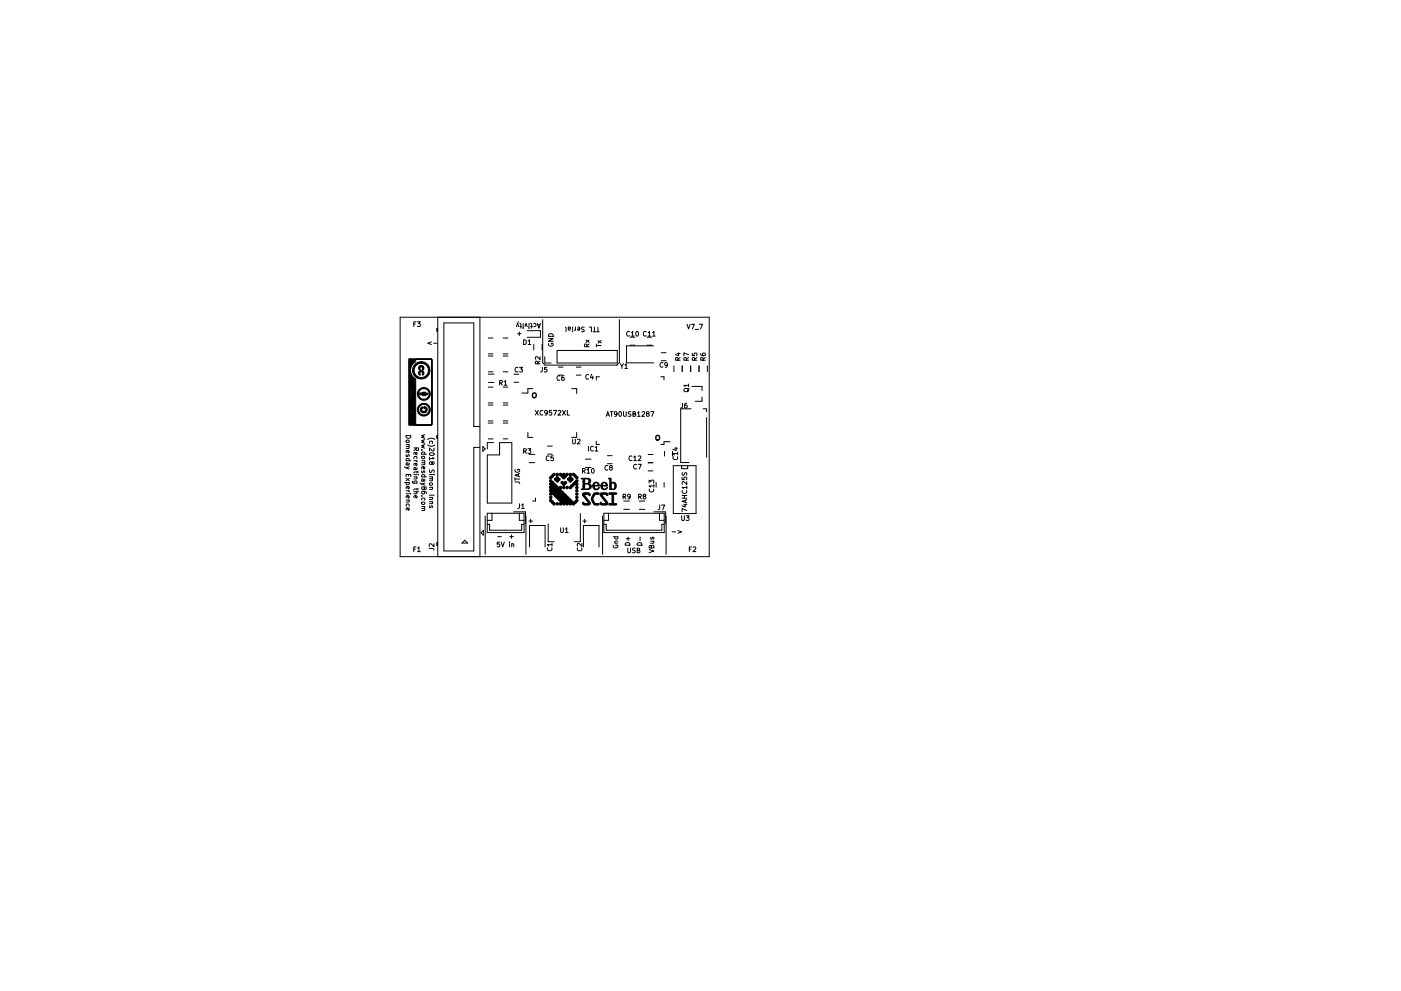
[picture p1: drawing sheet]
<svg xmlns="http://www.w3.org/2000/svg" width="297mm" height="210mm" viewBox="0 0 297 210" stroke-linecap="round" stroke-linejoin="round" font-family="sans-serif">
<g fill="none" stroke="#000" stroke-width=".21">
<path d="M84.8 67.3h65.6v50.8h-65.6zM87.7 68.8h.4M88.2 68.3h-.5v1M88.5 68.3h.6l-.3 .4 .3 .1v.4h-.6M91.5 72.5l-.8 .3 .8 .3M91.9 72.8h.8M92.7 69.7v.5M92.8 67.3v50.8M92.8 69.7h-.2v.5h.2M101.8 67.3v50.8M103.5 78.9h1M103.5 75.5h1"/>
<path d="M103.5 75.1h1M103.5 71.7h1M103.5 79.4h1.2M106.7 78.9h1M106.7 75.5h1M106.7 75.1h1M106.7 71.7h1M109 79.4h1M109.7 70.8h.8M109.7 68.6l.3 .7M109.8 78a.44 .44 0 0 0-.6 .4 .44 .44 0 0 0 .6 .4M110 68.3l-.5 1"/>
<path d="M110.1 70.4v.8M110.1 77.9h.7l-.4 .4 .3 .1v.4h-.6M110.2 68.6l.2 .2v.8M110.2 69.3h.4M110.9 69.5v.1M110.9 68.6v.7M111 72.1a.51 .51 0 0 1 .6 .5 .51 .51 0 0 1-.6 .5zM111.3 69.3l.2-.7 .3 .7M111.8 70.2h2.8v1.4h-2.8M112 72.4l.3-.3v1M112 73.1h.5M112.2 69.5v.1"/>
<path d="M112.2 68.6v.7M112.5 68.6l.2 .2v.8M112.5 69.3h.4M113.2 68.7l.2-.1 .2 .2-.1 .4h-.3M113.2 73.1v1.2M113.9 68.6l.4 1 .3-1M114 68.9h.5M114 77.2v-.5h-.4l-.1 .5h1M114.5 75.7v.6l-.7-.6-.3 .2 .1 .3M114.5 76.6l-.5 .3M114.9 73.1v1.2M115 77.9l-.1 .9-.3 .1"/>
<path d="M115.1 67.8v9.2l.5 .5h15.2l.5-.5v-9.2M115.5 75.7v1.3h1.3M115.9 77.9h-.4l-.1 .5h.5v.4h-.5M116.3 71.8h1l-1 .6h1M116.3 72.9a.45 .45 0 0 0 .5 .6 .45 .45 0 0 0 .4-.7h-.3v.2M116.3 71a.54 .54 0 0 1 .7-.2 .54 .54 0 0 1 .3 .6h-1zM118.1 74.4h12.8v2.6h-12.8zM118.4 79.6h1M118.4 77.9h1M118.7 79.8a.44 .44 0 0 0-.6 .4 .44 .44 0 0 0 .6 .4M119.6 79.7l-.5 .2v.6l.2 .2 .3-.1v-.5h-.3l-.2 .2M119.9 69.4l.1 .1v.9"/>
<path d="M120.5 69.4v.6h.4M120.5 69.4h.3l.2 .1-.1 .2-.4 .1M121.4 70.3v.1M121.4 69.4v.7M122 69.9l-.3 .2M122 69.4v.7M122.2 79.6h1M122.2 77.9h1M122.5 69.4h.3l.1 .1v.5h-.4l-.1-.2 .5-.1M123.9 69.4l-.6 .1a.42 .42 0 0 0 .5 .5v.3h-.5M124.2 72.1l.7 .6M124.4 73.6v-.5l-.4-.1-.1 .6h1"/>
<path d="M124.8 79.6a.44 .44 0 0 0-.6 .4 .44 .44 0 0 0 .6 .4M124.9 73l-.5 .3M124.9 72.1l-.7 .6M124.9 69.4h.5v1M125.4 79.4l-.2 .7h.6M125.7 79.8v.7M125.7 70.4h.6M126 69.4v1M126.5 73v.6M126.5 73.3h1M126.5 70.4h.6M126.8 69.4v1"/>
<path d="M126.8 72.2l.7 .6M127.1 79.9h-.7v.7M127.5 72.2l-.7 .6M131.5 77.2l.4 .5 .3-.5M131.9 77.7v.5M132.5 77.5l.3-.3v1M132.5 78.2h.5M133.5 70.4a.44 .44 0 0 0-.7 .4 .44 .44 0 0 0 .7 .4M133.6 71.5h1M133.6 73.2h1M133.9 70.6l.2-.3v1M133.9 71.3h.5"/>
<path d="M134.9 70.4l.1-.1a.49 .49 0 0 1 .4 .5 .49 .49 0 0 1-.5 .5l-.1-.4zM137 70.4a.44 .44 0 0 0-.6 .4 .44 .44 0 0 0 .6 .4M137.2 71.5h1M137.2 73.2h1M137.4 70.6l.3-.3v1M137.4 71.3h.6M138.4 70.6l.2-.3v1M138.4 71.3h.5M138.6 73.4h-5.8v3.6h5.8M140.1 79.9h.7v.7M140.2 76.5h1M140.2 74.8h1"/>
<path d="M140.5 77a.44 .44 0 0 0-.6 .4 .44 .44 0 0 0 .6 .4M141.5 77.3l-.2 .2h-.3v-.5l.3-.1 .2 .2v.6l-.5 .2M142.9 77.6v1.2M143.5 75h.7M143.7 76.4v-.5h-.4l-.1 .5h1M143.9 74.9v.6l-.7-.3M144.2 75.9l-.5 .3M144.6 77.6v1.2M145.5 76.4v-.5h-.4l-.1 .5h1M145.7 68.8l.3 1 .3-1M146 75.3l-1-.4v.6M146 75.9l-.5 .3"/>
<path d="M146.4 77.6v1.2M146.6 68.8h.6l-.4 1M146.8 74.9v.5l.4 .1v-.5l.5-.1v.6M147.3 76.4l-.1-.5h-.3l-.1 .5h1M147.4 69.9h.7M147.8 75.9l-.5 .3M148.2 77.6v1.2M148.3 68.8h.6l-.4 1M148.6 75l.2 .4 .6 .1 .2-.2-.1-.4-.5 .1-.1 .3 .2 .2M149.1 76.4l-.1-.5h-.4v.5h1M149.6 75.9l-.5 .3M150 77.6v1.2"/>
<path d="M85.8 99l1 .5M86.1 92.4h1a.51 .51 0 0 1-.5 .6 .51 .51 0 0 1-.5-.6zM86.1 97.8h1M86.1 94.3h.7M86.1 93.5l.5-.1 .2 .3-.2 .2h-.3l-.2-.2zM86.1 96.5v.3h.3l.2-.3 .2 .1-.1 .2M86.1 97.8v-.3l.2-.2 .4 .1v.4M86.1 98.7v-.4l.1-.1h.2l.1 .5M86.4 95.6l.1 .5 .2-.1 .1-.2-.2-.2-.5 .1v.3M86.6 94.8l.1 .3-.6 .1M86.7 94.3v.4l-.6 .1M86.7 98.2v.4l-.6 .1"/>
<path d="M86.8 99l-.7 .3M87.7 95h1v.6l-.4-.1-.1-.5M87.7 97.8h.7M87.8 97.3l-.1-.3 .2-.2 .5 .1v.4M88.1 96l.1 .5 .2-.1v-.3l-.1-.1h-.5v.4M88.1 98.3l.1 .5h.2v-.3l-.1-.2-.5 .1v.4M88.2 97.8l.2 .2M88.2 95.3l-.5 .3M88.4 99.2v.3l-.1 .2h-.6v-.4l.4-.1 .1 .5M88.4 100v.4M89.4 95.5h.1M89.4 96.4h1"/>
<path d="M89.4 97.8h.7M89.4 96.4v-.3l.2-.2 .4 .1v.4M89.4 96.9l.5-.1 .2 .3-.2 .2h-.3l-.2-.2zM89.4 99.9v.4h.3l.2-.4 .2 .1-.1 .3M89.7 99l.1 .5h.2l.1-.3-.2-.2-.5 .1v.4M89.9 98.2l.1 .4h-.6M90 97.8v.3l-.6 .1M90.1 92.2l-.7 .2 .5 .2-.5 .2 .7 .2M90.1 93.3l-.7 .2 .5 .2-.5 .1 .7 .2M90.1 94.3l-.7 .2 .5 .2-.5 .2 .7 .2M90.7 93.3a1.15 1.15 0 0 1 1.5 0M90.7 94.4a1.15 1.15 0 0 0 1.5 0"/>
<path d="M91 97v.6M91.1 94.1l-.1-.3 .2-.2 .5 .1v.4M91.1 96.2a.49 .49 0 0 1 .6-.2 .49 .49 0 0 1 .3 .5 .49 .49 0 0 1-.6 .2 .49 .49 0 0 1-.3-.5zM91.1 99.7v.5a.42 .42 0 0 0 .6-.5l.3 .1v.5M91.6 98.2l.4-.2v.4l-.3 .1-.3-.5-.4 .2 .2 .3 .4-.2M91.8 97l.2 .3h-1M92 95.1v.4l-.2 .2-.8-.6v.6M92.7 92.5v.5M92.8 92.5h-.2v.5h.2M101.8 90.5h-1.3v-22h-6.4v48.4h6.4v-22h1.3M102.4 94.7l.5 .5-.5 .6zM103.3 96.5h2.6v-2.6h2.6v12.8h-5.2z"/>
<path d="M103.5 89.3h1M103.5 85.9h1M103.5 85.5h1M103.5 82.1h1M103.5 93.1h1M103.5 89.8h1M103.5 81.1h1.2M104.6 93.9h-1.3v1.3M105.9 81.3l.5-.1 .1-.4-.6-.1v1M106.2 81.3l.3 .4M106.7 89.3h1M106.7 85.9h1"/>
<path d="M106.7 85.5h1M106.7 82.1h1M106.7 93.1h1M106.7 89.8h1M106.9 81l.3-.3v1M106.9 81.7h.6M109 81.1h1M109.2 99.6a.45 .45 0 0 0 .5 .6 .45 .45 0 0 0 .4-.6h-.3v.2M111 95.7h.5v-.4l-.5-.1v1M111.3 95.7l.3 .5M111.9 91.7v1.1h1.1M111.9 95.2h.6l-.3 .4 .3 .1v.4h-.6"/>
<path d="M112.2 96.4h1.2M112.2 98.2h1.2M113 82.4h-1.1v1h-1.3M113.5 87.1l.6 1M114.1 87.1l-.6 1M115.1 87.2a.44 .44 0 0 0-.6 .4 .44 .44 0 0 0 .6 .4M116 87.5l-.1 .2-.3-.1-.1-.4 .4-.1 .1 .2v.5l-.4 .3M116.1 96.3h1M116.1 94.6h1M116.4 96.8a.44 .44 0 0 0-.6 .4 .44 .44 0 0 0 .6 .4M117 87.1h-.5l-.1 .5 .5-.1 .1 .5h-.6M117.3 96.7h-.5v.5h.5v.4h-.5"/>
<path d="M117.3 87.1h.7l-.4 1M118.3 87.2l.4-.1 .2 .3-.6 .7h.6M119.2 87.1l.7 1M119.9 87.1l-.7 1M120.3 87.1v1h.5M121.2 82.4h1.1v1.1M121.4 93.2v.8l.2 .2 .4-.2v-.8M122.3 91.7v1.1h-1.1M122.4 93.3l.4-.1 .2 .3-.6 .7h.6M123.5 99.9h.5v-.4l-.5-.1v1M123.7 99.9l.4 .5M124.1 97.4h1.2"/>
<path d="M124.1 99.2h1.2M124.5 99.7l.2-.3v1M124.8 94.7v1M125.5 99.5l.1-.1a.49 .49 0 0 1 .4 .5 .49 .49 0 0 1-.5 .4l-.1-.3zM125.8 94.8a.44 .44 0 0 0-.6 .4 .44 .44 0 0 0 .6 .4M126.2 95l.3-.3v1M126.2 95.7h.6M126.4 93.6v.7h.7M128.5 88.3l.4-1 .3 1M128.6 88h.5M128.8 96.7h1M128.8 98.4h1"/>
<path d="M128.9 98.9a.44 .44 0 0 0-.7 .4 .44 .44 0 0 0 .7 .4M129.4 87.3h.6M129.4 99.2l-.1-.3 .4-.1 .1 .3-.6 .3 .2 .4 .4-.2-.2-.4M129.7 87.3v1M130.8 87.8l-.2 .1h-.3v-.5l.3-.1 .2 .2v.6l-.5 .2M131.3 87.4l.1-.1a.49 .49 0 0 1 .4 .5 .49 .49 0 0 1-.5 .5l-.1-.4zM132.2 87.3v.8l.2 .2 .4-.2v-.8M133.8 87.4h-.6a.42 .42 0 0 0 .5 .5v.4h-.5M134 96.8a.44 .44 0 0 0-.6 .4 .44 .44 0 0 0 .6 .4M134.2 87.8h.4l.1-.4-.5-.1v1h.4l.2-.3-.3-.2M134.4 97l.2-.3v1M134.4 97.7h.5"/>
<path d="M135 98.6a.44 .44 0 0 0-.7 .4 .44 .44 0 0 0 .7 .4M135.2 87.6l.2-.3v1M135.2 88.3h.5M135.3 98.5h.7l-.5 1M135.3 96.8l.4-.1 .2 .3-.6 .7h.6M136.1 87.4l.4-.1 .2 .3-.6 .7h.6M137.2 87.8l-.1-.4h.4l.1 .3-.5 .2 .1 .4 .4-.2-.2-.3M137.4 99.9h1M137.4 98.2h1M137.4 96.4h1M137.4 98.1h1M138 87.3h.6l-.4 1"/>
<path d="M140.9 95.8v1M142.1 93.7h-1.3v.6h-.7M142.6 95.8v1M142.7 98.8h4.9v10.2h-4.9zM142.8 96.9a.44 .44 0 0 0 .4 .6 .44 .44 0 0 0 .4-.6M143 95.1h.7M143.4 95v.6l-.8-.3M143.7 96.2h-1l.3 .3M143.7 96v.5M144.5 98.8v.6h1.3v-.6M144.7 85.6v.8l-.4 .2M145 82.6l.3-.2 .6 .1 .1 .4-.3 .2h-.6z"/>
<path d="M145.6 85.6l-.4 .2-.1 .6 .2 .2 .4-.1-.1-.5-.3-.1-.2 .2M146 81.8h-1l.3 .3M146 81.5v.6M146.1 82.4l-.3 .5M146.5 86.7h-2.2v11.4h1.8M146.7 82h2.1v.9M148.8 84.2v.9h-1.4M149.1 86.7h.7v.7M149.8 88.6v8.4M85.8 102.4h1M86.1 101.1v-.4h1v.4M86.1 101.5l.7 .5"/>
<path d="M86.1 104.1h.7M86.1 104.8h.7M86.1 106.1h.7M86.1 102.4v.3l.2 .1h.4v-.4M86.1 107.4v-.3l.2-.2 .4 .1v.4M86.4 103.2l.1 .5h.2l.1-.3-.2-.2-.5 .1v.4M86.4 105.2l.1 .5 .2-.1 .1-.3-.2-.1h-.5v.4M86.4 107.8l.1 .5 .2-.1 .1-.3-.2-.1h-.5v.4M86.6 104.1l.2 .3M86.6 100.7v.3M86.7 106.1v.4h-.6M86.8 101.5l-.7 .5"/>
<path d="M87 104.8h.1M87.5 102.1l-.1 .2 .2 .2h.8M87.7 116.5h.4M87.7 101.2h.7M87.7 100.7h.7M87.7 104.3h1M87.8 102.5l-.1-.3 .2-.2 .5 .1v.4M88.1 105.2l.1 .5 .2-.1v-.3l-.1-.1h-.5v.4M88.2 116h-.5v1M88.3 101.2l.1 .4h-.7M88.3 104.3l.1 .4-.7 .1M88.4 103.6v.4"/>
<path d="M88.5 116.3l.3-.3v1M88.5 117h.6M88.7 100.7h.1M88.7 100.1h-.8l-.2 .3M88.7 103.8h-.8l-.2 .2M89.1 102.5l1 .4M89.4 105.2h.1M89.4 101.2h1M89.4 107.5h.7M89.4 101.2v-.3l.2-.2 .4 .1v.4M89.4 102.1v-.3l.1-.2 .2 .1 .1 .4M89.4 106.1v-.3l.2-.1 .4 .1v.3"/>
<path d="M89.4 106.6l.5-.1 .2 .3-.2 .2h-.3l-.2-.2zM89.8 104.2l.2 .2v.3l-.5 .1-.1-.4 .2-.2 .6 .1 .2 .4M89.9 107.9l.1 .4h-.6M90 103.5l.3-.2 .1 .5h-.3l-.3-.5-.4 .2 .2 .3 .4-.1M90 107.5v.3l-.6 .1M90 101.7v.3l-.6 .1M90.1 102.5l-.7 .2M91 116.4h.9l.1 .3M91 100.7h.7M91 101.2h.7M91 103.4h.7M91 105.1h1"/>
<path d="M91 105.5h.7M91 106.4h.7M91.1 107.3v.4h.2l.2-.4 .2 .1v.3M91.1 102.5h.5l.1 .4h-.6zM91.6 101.6l.1 .4h-.7M91.6 101.2l.1 .3-.7 .1M91.6 103.4l.1 .4h-.7M91.6 105.5l.1 .4-.7 .1M91.6 106.4l.1 .4-.7 .1M92 100.7h.1M92 115.4v.6l-.7-.6-.3 .1 .1 .4M92.7 115.2v.5"/>
<path d="M92.8 115.2h-.2v.5h.2M98.6 114.6l.6 .6h-1.2zM102.5 112.5v1l-.5-.5zM102.9 109.5v8.1M103.3 108.9h7.8v4.1h-7.8zM103.3 111.2h.5v1.3h6.8v-1.3h.5M104.3 108.9v1.5h-1M105.5 113.9h.8M105.9 115h-.5v.5l.5-.1v.5h-.5M106.3 115l.3 1 .3-1M108 115v.1M108 115.3v.7"/>
<path d="M108.1 113.9h.7M108.5 113.5v.7M108.5 115.4h.4v.6M108.5 115.3v.7M108.9 108.6h2.5v2.5M109.2 102.3h.8l.2 .3M109.2 101.3v.6M109.2 101.6h1M109.9 100.6v.5M110.1 108.9v1.5h1M110.2 106.9l-.1 .8-.3 .2M110.2 100.5l-1 .3 1 .4"/>
<path d="M110.6 107.2l.3-.3v1M110.6 107.9h.6M111.5 109.5v8.1M112.1 110.6h.8M112.3 116v-4.5h3.3v4.5M112.5 110.2v.7M113.5 105.7v.6h-.6M116.1 116.2a.44 .44 0 0 0 .4 .7 .44 .44 0 0 0 .4-.7M116.2 111.2v3.7h1.3M117 115.6h-1l.3 .3M117 115.3v.6M118.9 112v.8l.2 .2 .3-.2v-.8"/>
<path d="M119.9 112.3l.3-.3v1M119.9 113h.5M122.5 116.2a.44 .44 0 0 0 .4 .7 .44 .44 0 0 0 .4-.7M123 108.9v6h-1.2M123.4 115.3v.6l-.7-.6-.3 .2 .1 .4M123.6 110.6h.7M123.7 116v-4.5h3.3v4.5M124 110.2v.7M124.5 100.4h.5M127.8 109.5v8.1M128 108.9h12.8v4.1h-12.8zM128 111.2h.5v1.3h11.8v-1.3h.5"/>
<path d="M129 108.9v1.5h-1M130 113.9h1M130.1 115.7a.45 .45 0 0 0 .4 .6 .45 .45 0 0 0 .4-.6h-.3v.1M130.3 115.2h.7M130.4 113.9l-.1 .3 .2 .2 .5-.1v-.4M131 114.8h-.6v.4M132.1 105.4l.5-.1v-.3l-.5-.1v1M132.2 108.1h1.2M132.2 106.3h1.2M132.3 105.4l.4 .5M132.6 115.3a.54 .54 0 0 1 .6-.2 .54 .54 0 0 1 .3 .6h-1zM132.8 114.3h.7"/>
<path d="M133.1 116.3v.8l.2 .2 .4-.2v-.8M133.2 113.9v.8M133.6 105.3l-.2 .2-.2-.1-.1-.4 .3-.1 .2 .1v.6l-.4 .3M134.7 116.3l-.5 .1a.42 .42 0 0 0 .4 .5v.3h-.5M135.1 116.8l.4-.1 .1-.3-.5-.1v1h.4l.2-.3-.3-.2M135.1 115.3a.54 .54 0 0 1 .7-.2 .54 .54 0 0 1 .3 .6h-1zM135.4 105.4l.5-.1v-.3l-.5-.1v1M135.5 108.1h1.2M135.5 106.3h1.2M135.6 105.4l.4 .5M135.7 113.9v.8M136.5 105.3l-.1-.3 .4-.1 .1 .3-.5 .3 .1 .4 .4-.2-.2-.4"/>
<path d="M137.6 116.6l1 .3-1 .4M137.6 102.5v-.6l.4 .3 .1-.3h.4v.6M137.7 103.8a.44 .44 0 0 0 .4 .6 .44 .44 0 0 0 .4-.6M138 114.8h.6M138 114l.1 .4 .2-.4h.3v.4M138.1 115.9l.2-.2 .3 .2v.4h-1l.1-.5h.4v.5M138.5 114.8l.1 .4-.6 .1M138.6 108.6h2.5v2.5M138.6 103.1h-1l.3 .3M138.6 102.8v.6M139.1 102.4v1M139.8 108.9v1.5h1"/>
<path d="M139.9 107.1l-.1 .9-.3 .1M140.3 107.1h.6l-.4 1M140.8 102.4v1M141.2 109.5v8.1M142.5 112.8h.8M143.7 112.6l.8 .2-.8 .3M144.5 109.4v.8l.2 .2 .4-.2v-.8M144.6 101.3v.4l.5 .1-.1-.5h.5v.5M144.6 105.7h1M144.6 105.1h1M144.7 100.3v.5a.42 .42 0 0 0 .5-.5l.4 .1v.4M144.7 104.1a.44 .44 0 0 0 .4 .6 .44 .44 0 0 0 .4-.6"/>
<path d="M144.9 107.1h.7M145.1 105.1v.6M145.3 106.9v.7l-.7-.3M145.3 106.1v.5M145.5 109.4h.6l-.3 .4 .2 .1v.4h-.5M145.6 108.3l-1-.4v.7M145.6 106l-1 .4 1 .3M145.6 103.4h-1l.3 .3M145.6 102.2v.6l-.7-.6-.3 .2 .1 .3M145.6 103.1v.6M146.1 116.5h.4M146.6 116h-.5v1"/>
<path d="M147 116.1l.3-.1 .2 .3-.6 .7h.6"/>
</g>
<path d="M113 83.5l.2-.1 .4 .1 .1 .6-.2 .2-.3 .1-.2-.2zM139.1 92.5l.2-.1 .5 .1v.6l-.1 .2-.4 .1-.2-.2z" fill="none" stroke="#000" stroke-width=".3"/>
<g fill="#000" stroke="#000" stroke-width=".21">
<path d="M88.9 78.8a.53 .53 0 0 1 .8-.1 .53 .53 0 0 1-.1 .8l-.1-.1a.29 .29 0 0 0 .1-.4 .29 .29 0 0 0-.4 0 .29 .29 0 0 0-.1 .4l-.1 .2-.2-.2zM88.9 77.7a.57 .57 0 0 1 .8 0 .57 .57 0 0 1-.1 .9l-.1-.2a.29 .29 0 0 0 .1-.4 .29 .29 0 0 0-.4-.1 .29 .29 0 0 0-.1 .4v.2a.43 .43 0 0 1-.4-.3 .43 .43 0 0 1 .2-.5zM88.1 77.3l.9-.5h.3v.3a1.52 1.52 0 0 0-1.3 2.3 1.52 1.52 0 0 0 2.7 0 1.52 1.52 0 0 0-1.3-2.3l-.1-.3a1.83 1.83 0 0 1 1.8 2.3 1.83 1.83 0 0 1-2.7 1.1 1.83 1.83 0 0 1-.3-2.9zM87.1 83h.2l-.1 .3zM87.3 87l.2 .1-.2 .1zM87.4 83h.2l-.1 .3zM89 83.4l.9-.2a.26 .26 0 0 1 .4 0 .26 .26 0 0 1 0 .4l-.1 .3h-.6v-.1h-.6zM89.3 86.4l.3-.1v.3a.38 .38 0 0 0-.1 .6 .38 .38 0 0 0 .6 0 .28 .28 0 0 0 .2-.3 .28 .28 0 0 0-.3-.2l-.2-.2 .2-.3 .1 .1a.71 .71 0 0 1 .3 1.1 .71 .71 0 0 1-1.1 .1 .71 .71 0 0 1 0-1.1zM88.9 86l.7-.4h.3v.2a1.13 1.13 0 0 0-1 1.6 1.13 1.13 0 0 0 1.9 .2 1.13 1.13 0 0 0-.7-1.8h-.2v-.2a1.36 1.36 0 0 1 1.3 1.7 1.36 1.36 0 0 1-2 .8 1.36 1.36 0 0 1-.3-2.1zM88.9 82.7l.7-.5h.2v.3a1.13 1.13 0 0 0-.9 1.6 1.13 1.13 0 0 0 1.9 .1 1.13 1.13 0 0 0-.8-1.7h-.2v-.3a1.36 1.36 0 0 1 1.4 1.7 1.36 1.36 0 0 1-2 .9 1.36 1.36 0 0 1-.3-2.1zM86.7 76.1h.3v7.1l.2 .3 .5-.1 .1-.2v.3l-.8 .3v.2h.2v2.1l-.3 .3 .2 .9-.1 .2 .4-.1a.25 .25 0 0 0 .4-.3 .24 .24 0 0 0-.4-.2l-.4-.1v-.2a.36 .36 0 0 0 .4 0 .36 .36 0 0 0 .2-.3l-.1 .4a.28 .28 0 0 0 .3-.3 .28 .28 0 0 0-.4-.3 .28 .28 0 0 0-.2 .4h-.1l.1-.3v-2.2l.6 .2v-.2l-.3-.1 .2-.2 .1-.9h-.8v-6.7h4.4l-3.3 .1v.5a2.09 2.09 0 0 0 0 3.7v9.7h3.3v-14l.1 .1 .1 13v.8l-.1 .2h-4.8zM116.6 106h.3l.1 .3h.3v.4l.4 .1-.1 .3h-.3l-.1-.3-.3-.1v-.3l-.4-.1z"/>
<path d="M116.6 101.9h.3l.1 .3h.3v.3l.4 .1v.2l.3 .1v.3l.4 .1v.2h.2l.1-.3h.3l.1 .3-.4 .2v.2h.3l.1 .3 .3 .1v.3h.3l.1 .3 .2 .1 .1 .3 .4 .1v.2l.3 .1v.3h.3l.1 .3 .3 .1v.3h.2l.1-.3 .3-.1 .1-.3h.3v.4h-.3v.3l-.3 .1-.2 .4-.3-.1v-.3h-.2l-.2 .4-.3-.1v-.3h-.2l-.2 .4-.3-.1v-.3h-.2l-.2 .4-.3-.1v-.3h-.2l-.2 .3h-.2l-.1-.3 .4-.1v-.3h.4v.3h.2v-.3h.5v.3h.2v-.3h.5v.3h.2v-.3h-2.3l-.1-.3h.5v.2h.2v-.2h.5v.2h.2v-.2h.5v.2h.2v-.2h-2.3l-.1-.4h.4v.3h.3v-.3h.4v.3h.2v-.3h.5v.3h.2v-.3l-2.2 .1-.2-.4h.5v.2h.2v-.2h.5v.2h.2v-.2h.5v.2h.2v-.2h-2.3l-.1-.3h.4v.2h.3v-.2h.4v.2h.3v-.2h.4v.2h.2v-.2h-2.2l-.2-.2v-.2h.5v.2h.2v-.2h.5v.2h.2v-.2h.5v.2h.2v-.2h-2.3l-.1 .3h-.3l-.1-.3 .4-.1v-.2h.4v.2h.3v-.2h.4v.2h.3v-.2h.4v.2h.3v-.2l-2.4-.1-.1-.3h.5v.2h.2v-.2h.5v.2h.2v-.2h.5v.2h.2v-.2h-2.1l.4-.1v-.2h.4v.2h.3v-.2h.4v.2h.3v-.2l-1.7-.1-.1-.3h.5v.2h.2v-.2h.5v.2h.2v-.2h-1.4l.4-.1v-.2h.4v.2h.3v-.2l-1-.1-.1-.3h.5v.2h.2v-.2h-.7l.4-.1v-.2l-.4-.2zM116.9 100.8h.3l.2-.4 .3 .2-.1 .3h-.3v.3h-.3v.3l-.3 .1-.2-.3 .4-.2zM118 101.2l.3-.1 .1 .4 .4 .1-.6 .7-.7-.5 .1-.2h.4v.2h.3v-.2h-.7l.3-.1zM119 102.2h.3l.1 .3h.2l.1-.3 .2-.1 .2 .3-.6 .6-.2-.4-.3-.1zM118.7 100.5l.2-.1 .2 .4h.2v-.3l.3-.1 .2 .4h.2v-.3l.3-.1 .2 .3-1 .9-.6-.7h.5v.2h.2v-.2h-.9l-.1-.2zM120.7 101.2l.4-.1 .1 .4 .3 .2-.5 .6-.7-.5v-.2h.5v.2h.2v-.2h-.7l.4-.1zM121.4 100.5h.4l.1 .3h.2l.1 .3 .3 .1v.3l-.3 .1-.1-.4h-.3l-.1-.3-.3-.1zM121.8 102.2h.3l.1-.4 .3 .1v.2l-.3 .2v.2l.3 .1v.3l-.3 .1-.1-.4h-.2l-.1 .3-.3 .1-.1 .3h-.2l-.1 .3-.3 .1-.1-.4 .3-.1 .1-.3 .3-.1 .1-.3h.2zM123.2 101.5h1.5l.4 .2 .1 .5-.5 .4 .6 .4-.1 .6-.6 .3h-1.4v-.2h.4v-.5h.4v.4l.1 .1h.7l.2-.5-.2-.4-.3-.1h-.5v.5h-.4v-1.1h.4v.5h.5l.3-.3v-.4l-.2-.3h-.5l-.1 .5h-.4v-.4l-.4-.1zM123.6 104.7l1.2-.1 .3 .2-.1 .4-.3-.3h-.9l1.3 1.7v.3l-.1 .2-1.1 .1-.4-.3v-.2l.1-.2 .3 .3h.9l-1.3-1.7zM125.9 104.7l.3-.2 .8 .2-.1 .2h-.7l-.5 .9 .4 1h.8v.3h-.9l-.6-.9v-.6zM125.9 102.5l.6-.2 .4 .3 .2 .5h-1.1l.1 .5 .2 .1 .8-.2-.3 .3-.5 .1-.5-.3-.1-.6h1l.1-.1-.2-.4-.3-.1-.2 .2-.1 .4h-.3z"/>
<path d="M127.3 104.7l1.2-.1 .3 .2v.4l-.3-.3h-.9l1.2 1.7 .1 .3-.2 .2-1.1 .1-.3-.3-.1-.2 .2-.2 .2 .3h1l-1.3-1.7zM127.6 102.5l.6-.2 .4 .3 .2 .5h-1.1l.1 .5 .3 .1 .7-.2-.3 .3-.5 .1-.4-.3-.2-.6h1l.1-.1-.1-.4-.3-.1-.3 .2-.1 .4h-.3zM129 101.5l.6-.1v1.2l.6-.3 .4 .5-.1 .8-.4 .3-.4-.1a.21 .21 0 0 0-.2-.1 .21 .21 0 0 0-.2 .2v-.8h.3l.1 .5 .3 .2 .3-.3v-.6l-.1-.4h-.3l-.3 .1v.5h-.3v-1.4zM129.1 104.6h1.6l-.1 .3h-.5v1.9h.6v.3h-1.6l.1-.3h.6v-1.9h-.6z"/>
<circle cx="90.6" cy="83.6" r=".18"/>
<circle cx="116.8" cy="105.5" r=".26"/>
<circle cx="118.2" cy="100.7" r=".26"/>
<circle cx="118.2" cy="106.9" r=".26"/>
<circle cx="119.5" cy="103.4" r=".26"/>
<circle cx="120.2" cy="103.4" r=".26"/>
<circle cx="120.9" cy="100.7" r=".26"/>
<circle cx="122.3" cy="104.8" r=".26"/>
<circle cx="122.3" cy="105.5" r=".26"/>
<circle cx="122.3" cy="103.4" r=".26"/>
<circle cx="122.3" cy="104.1" r=".26"/>
</g>
</svg>
